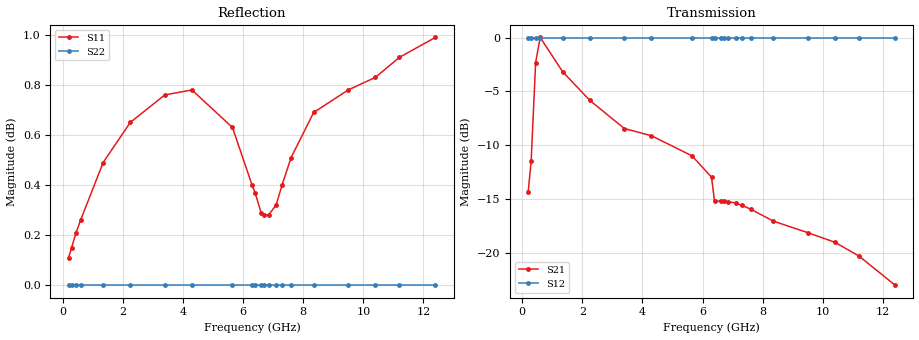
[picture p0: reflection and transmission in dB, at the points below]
# hz S db R 100
! AFE7900 - TX Channel A, DSA = 20dB, Fs = 11.79648 GHz
! 4/8/20
! Port 1 - SE representation of DAC differential output
! Port 2 - DAC analogoutput
! freq  dbS11  angS11
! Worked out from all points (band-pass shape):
!   245 points, 200 MHz to 12.4 GHz, reference 100 ohm
!   highest |S21| = 0.02 dB at 600 MHz (marker M1); lowest = -23.0 dB at 12.4 GHz (marker M2)
!   |S21| within 3 dB of the highest: 436.4 MHz to 1.306 GHz (869.6 MHz wide, 99.8 % of centre)
!   lowest |S11| = 0.1 dB at 200 MHz (marker M3)
!   |S11| at or under -10 dB: nowhere
!   |S22| runs from 0.0 to 0.0 dB; largest |S21 - S12| = 0.93
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2e8  0.11 -77.3  -14.41 0.0  0.00 0.0  0.00 0.0
3e8  0.15 -87.3  -11.52 0.0  0.00 0.0  0.00 0.0
4.5e8  0.21 -97.5  -2.32 0.0  0.00 0.0  0.00 0.0
6e8  0.26 -104.6  0.02 0.0  0.00 0.0  0.00 0.0
1.35e9  0.49 -129.9  -3.18 0.0  0.00 0.0  0.00 0.0
2.25e9  0.65 -154.8  -5.84 0.0  0.00 0.0  0.00 0.0
3.4e9  0.76 178.5  -8.46 0.0  0.00 0.0  0.00 0.0
4.3e9  0.78 165.7  -9.13 0.0  0.00 0.0  0.00 0.0
5.65e9  0.63 146.7  -11.00 0.0  0.00 0.0  0.00 0.0
6.3e9  0.40 117.6  -12.99 0.0  0.00 0.0  0.00 0.0
6.4e9  0.37 109.0  -15.24 0.0  0.00 0.0  0.00 0.0
6.6e9  0.29 88.6  -15.21 0.0  0.00 0.0  0.00 0.0
6.7e9  0.28 70.7  -15.18 0.0  0.00 0.0  0.00 0.0
6.85e9  0.28 44.8  -15.27 0.0  0.00 0.0  0.00 0.0
7.1e9  0.32 9.4  -15.38 0.0  0.00 0.0  0.00 0.0
7.3e9  0.40 -10.4  -15.60 0.0  0.00 0.0  0.00 0.0
7.6e9  0.51 -27.2  -15.96 0.0  0.00 0.0  0.00 0.0
8.35e9  0.69 -52.5  -17.07 0.0  0.00 0.0  0.00 0.0
9.5e9  0.78 -86.3  -18.15 0.0  0.00 0.0  0.00 0.0
1.04e10  0.83 -120.2  -19.04 0.0  0.00 0.0  0.00 0.0
1.12e10  0.91 -144.9  -20.32 0.0  0.00 0.0  0.00 0.0
1.24e10  0.99 -157.9  -23.03 0.0  0.00 0.0  0.00 0.0
